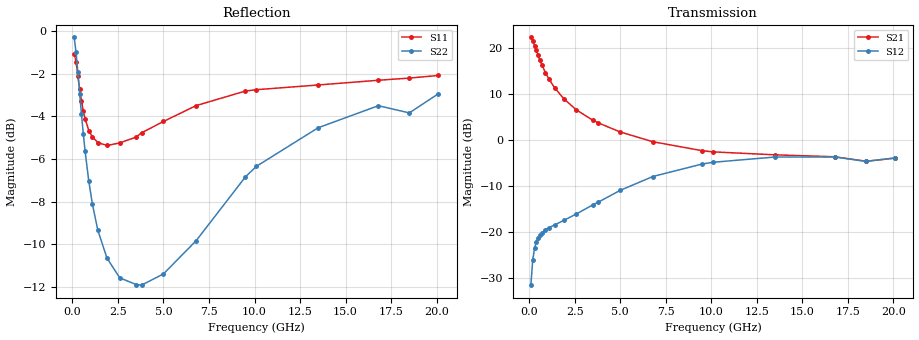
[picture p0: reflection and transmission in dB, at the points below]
!  Infineon Technologies AG
! BFR380L3 , PF131585-7, No.6, Th 09.10.01, soldered on pcb-board, measured with PP GSG850
!  Vce=5.0 V,  Ic=4.0 mA
! Common Emitter S-Parameters:  15. November 2001
#  GHz  S  MA  R  50
! f  S11  S21  S12  S22
! GHz  Mag  Ang  Mag  Ang  Mag  Ang  Mag  Ang
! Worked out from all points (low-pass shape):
!   201 points, 100 MHz to 20.1 GHz, reference 50 ohm
!   highest |S21| = 22.25 dB at 100 MHz (marker M1); lowest = -4.7 dB at 18.5 GHz (marker M2)
!   |S21| within 3 dB of the highest: start of sweep to 414.3 MHz
!   lowest |S11| = -5.4 dB at 1.9 GHz (marker M3), VSWR 3.34, Z = 15 - j2.38 ohm
!   |S11| at or under -10 dB: nowhere
!   |S22| runs from -11.9 to -0.3 dB; largest |S21 - S12| = 13
!   S11 on the Smith chart (normalised r, x): 100 MHz: 1.35, -4.39; 400 MHz: 0.37, -1.13; 1.1 GHz: 0.31, -0.31; 3.8 GHz: 0.29, +0.28; 9.5 GHz: 0.36, +1.08; 20.1 GHz: 0.99, +2.53
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0.1  0.8846 -23.6  12.95 164.0  0.0262 76.7  0.9657 -13.1
0.2  0.8467 -44.7  11.81 150.0  0.04884 66.5  0.8917 -24.8
0.3  0.7847 -63.7  10.56 138.0  0.06569 58.4  0.8001 -34.0
0.4  0.7314 -79.5  9.334 128.3  0.07758 51.8  0.7124 -41.1
0.5  0.6861 -93.0  8.237 120.5  0.08605 47.4  0.6369 -46.4
0.6  0.6483 -104.3  7.311 114.1  0.09238 44.4  0.5736 -50.4
0.7  0.6224 -114.2  6.554 108.5  0.09723 42.2  0.5217 -53.5
0.9  0.584 -129.9  5.369 99.8  0.1048 39.9  0.4447 -57.9
1.1  0.564 -142.1  4.539 92.9  0.1106 39.2  0.3924 -61.3
1.4  0.5474 -156.4  3.672 84.4  0.1182 39.8  0.3405 -65.0
1.9  0.5388 -174.0  2.794 73.0  0.1323 42.5  0.2933 -70.8
2.6  0.5463 168.3  2.108 60.1  0.1557 46.4  0.2637 -80.5
3.5  0.5638 150.4  1.626 46.0  0.1954 49.9  0.2543 -94.9
3.8  0.5769 145.8  1.522 42.2  0.2091 50.3  0.2535 -101.5
5  0.6134 127.8  1.214 27.4  0.2808 49.0  0.2693 -124.9
6.8  0.6683 106.0  0.9498 10.9  0.3976 40.3  0.3224 -162.5
9.5  0.7228 82.0  0.7589 -4.2  0.5434 21.2  0.4547 153.1
10.1  0.7281 77.7  0.7368 -6.7  0.5679 16.8  0.4813 144.4
13.5  0.7469 59.2  0.684 -20.1  0.6474 -7.0  0.593 106.7
16.8  0.7662 47.5  0.6514 -31.2  0.6475 -24.3  0.6678 81.3
18.5  0.7752 45.6  0.5827 -39.1  0.5805 -33.0  0.6424 74.6
20.1  0.7863 38.5  0.6288 -42.7  0.6338 -38.4  0.7126 63.3
